VERSION 5.7 ;
  NOWIREEXTENSIONATPIN ON ;
  DIVIDERCHAR "/" ;
  BUSBITCHARS "[]" ;
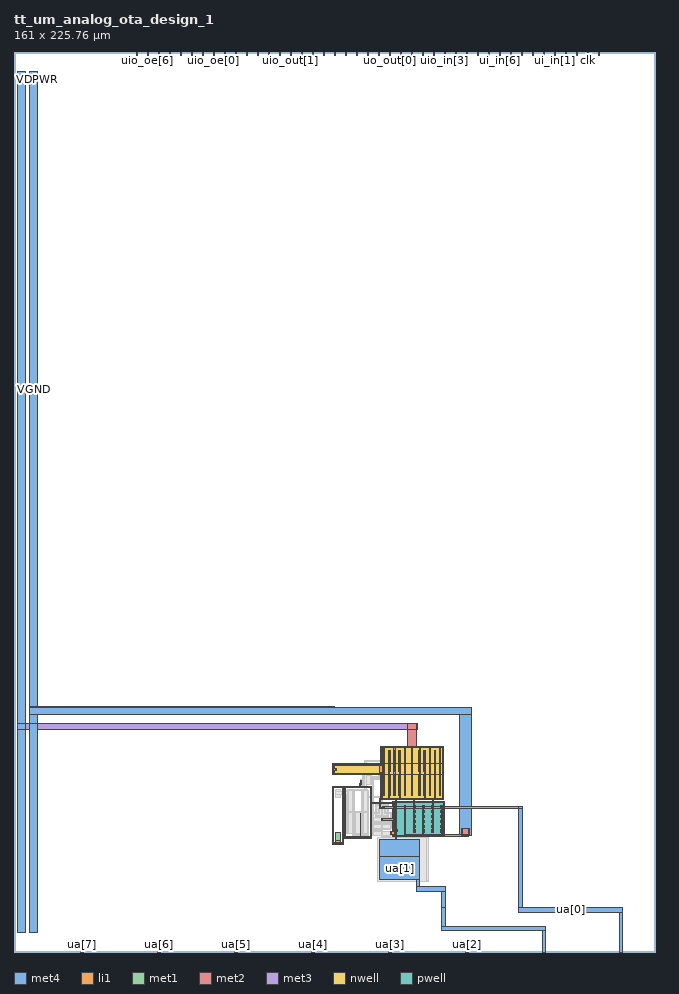
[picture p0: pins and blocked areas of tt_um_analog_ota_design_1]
MACRO tt_um_analog_ota_design_1
  CLASS BLOCK ;
  FOREIGN tt_um_analog_ota_design_1 ;
  ORIGIN 0.000 0.000 ;
  SIZE 161.000 BY 225.760 ;
  PIN clk
    DIRECTION INPUT ;
    USE SIGNAL ;
    PORT
      LAYER met4 ;
        RECT 143.830 224.760 144.130 225.760 ;
    END
  END clk
  PIN ena
    DIRECTION INPUT ;
    USE SIGNAL ;
    PORT
      LAYER met4 ;
        RECT 146.590 224.760 146.890 225.760 ;
    END
  END ena
  PIN rst_n
    DIRECTION INPUT ;
    USE SIGNAL ;
    PORT
      LAYER met4 ;
        RECT 141.070 224.760 141.370 225.760 ;
    END
  END rst_n
  PIN ua[0]
    DIRECTION INOUT ;
    USE SIGNAL ;
    ANTENNAGATEAREA 0.625000 ;
    PORT
      LAYER li1 ;
        RECT 92.460 36.145 92.960 36.315 ;
      LAYER met1 ;
        RECT 92.535 36.345 92.895 36.360 ;
        RECT 92.480 36.115 92.940 36.345 ;
        RECT 92.535 36.100 92.895 36.115 ;
      LAYER met2 ;
        RECT 92.585 36.040 92.865 36.420 ;
      LAYER met3 ;
        RECT 92.535 36.065 127.590 36.395 ;
        RECT 126.580 36.060 127.590 36.065 ;
      LAYER met4 ;
        RECT 126.625 36.055 127.545 36.400 ;
        RECT 126.630 11.280 127.530 36.055 ;
        RECT 126.630 11.180 133.390 11.280 ;
        RECT 126.630 10.010 152.705 11.180 ;
        RECT 151.810 0.000 152.710 10.010 ;
    END
  END ua[0]
  PIN ua[1]
    DIRECTION INOUT ;
    USE SIGNAL ;
    ANTENNAGATEAREA 0.625000 ;
    ANTENNADIFFAREA 15.688999 ;
    PORT
      LAYER li1 ;
        RECT 94.070 45.245 94.240 50.585 ;
        RECT 96.650 45.245 96.820 50.585 ;
        RECT 102.930 45.245 103.100 50.585 ;
        RECT 105.510 45.245 105.680 50.585 ;
        RECT 94.070 39.305 94.240 44.645 ;
        RECT 96.650 39.305 96.820 44.645 ;
        RECT 102.930 39.305 103.100 44.645 ;
        RECT 105.510 39.305 105.680 44.645 ;
        RECT 91.670 36.145 92.170 36.315 ;
        RECT 95.755 36.015 95.925 36.705 ;
        RECT 100.335 36.015 100.505 36.705 ;
        RECT 104.915 36.015 105.085 36.705 ;
        RECT 95.755 34.815 95.925 35.505 ;
        RECT 100.335 34.815 100.505 35.505 ;
        RECT 104.915 34.815 105.085 35.505 ;
        RECT 95.755 33.615 95.925 34.305 ;
        RECT 100.335 33.615 100.505 34.305 ;
        RECT 104.915 33.615 105.085 34.305 ;
        RECT 95.755 32.415 95.925 33.105 ;
        RECT 100.335 32.415 100.505 33.105 ;
        RECT 104.915 32.415 105.085 33.105 ;
        RECT 95.755 31.215 95.925 31.905 ;
        RECT 100.335 31.215 100.505 31.905 ;
        RECT 104.915 31.215 105.085 31.905 ;
        RECT 95.755 30.015 95.925 30.705 ;
        RECT 100.335 30.015 100.505 30.705 ;
        RECT 104.915 30.015 105.085 30.705 ;
      LAYER met1 ;
        RECT 94.040 50.550 94.270 50.565 ;
        RECT 96.620 50.550 96.850 50.565 ;
        RECT 102.900 50.550 103.130 50.565 ;
        RECT 105.480 50.550 105.710 50.565 ;
        RECT 93.975 45.280 94.335 50.550 ;
        RECT 96.555 45.280 96.915 50.550 ;
        RECT 102.835 45.280 103.195 50.550 ;
        RECT 105.415 45.280 105.775 50.550 ;
        RECT 94.040 45.265 94.270 45.280 ;
        RECT 96.620 45.265 96.850 45.280 ;
        RECT 102.900 45.265 103.130 45.280 ;
        RECT 105.480 45.265 105.710 45.280 ;
        RECT 94.040 44.610 94.270 44.625 ;
        RECT 96.620 44.610 96.850 44.625 ;
        RECT 102.900 44.610 103.130 44.625 ;
        RECT 105.480 44.610 105.710 44.625 ;
        RECT 93.975 39.340 94.335 44.610 ;
        RECT 96.555 39.340 96.915 44.610 ;
        RECT 102.835 39.340 103.195 44.610 ;
        RECT 105.415 39.340 105.775 44.610 ;
        RECT 94.040 39.325 94.270 39.340 ;
        RECT 96.620 39.325 96.850 39.340 ;
        RECT 102.900 39.325 103.130 39.340 ;
        RECT 105.480 39.325 105.710 39.340 ;
        RECT 95.725 36.625 95.955 36.685 ;
        RECT 100.305 36.625 100.535 36.685 ;
        RECT 104.885 36.625 105.115 36.685 ;
        RECT 91.735 36.345 92.095 36.360 ;
        RECT 91.690 36.115 92.150 36.345 ;
        RECT 91.735 36.100 92.095 36.115 ;
        RECT 95.660 36.095 96.020 36.625 ;
        RECT 100.240 36.095 100.600 36.625 ;
        RECT 104.820 36.095 105.180 36.625 ;
        RECT 95.725 36.035 95.955 36.095 ;
        RECT 100.305 36.035 100.535 36.095 ;
        RECT 104.885 36.035 105.115 36.095 ;
        RECT 95.725 35.425 95.955 35.485 ;
        RECT 100.305 35.425 100.535 35.485 ;
        RECT 104.885 35.425 105.115 35.485 ;
        RECT 95.660 34.895 96.020 35.425 ;
        RECT 100.240 34.895 100.600 35.425 ;
        RECT 104.820 34.895 105.180 35.425 ;
        RECT 95.725 34.835 95.955 34.895 ;
        RECT 100.305 34.835 100.535 34.895 ;
        RECT 104.885 34.835 105.115 34.895 ;
        RECT 95.725 34.225 95.955 34.285 ;
        RECT 100.305 34.225 100.535 34.285 ;
        RECT 104.885 34.225 105.115 34.285 ;
        RECT 95.660 33.695 96.020 34.225 ;
        RECT 100.240 33.695 100.600 34.225 ;
        RECT 104.820 33.695 105.180 34.225 ;
        RECT 95.725 33.635 95.955 33.695 ;
        RECT 100.305 33.635 100.535 33.695 ;
        RECT 104.885 33.635 105.115 33.695 ;
        RECT 95.725 33.025 95.955 33.085 ;
        RECT 100.305 33.025 100.535 33.085 ;
        RECT 104.885 33.025 105.115 33.085 ;
        RECT 95.660 32.495 96.020 33.025 ;
        RECT 100.240 32.495 100.600 33.025 ;
        RECT 104.820 32.495 105.180 33.025 ;
        RECT 95.725 32.435 95.955 32.495 ;
        RECT 100.305 32.435 100.535 32.495 ;
        RECT 104.885 32.435 105.115 32.495 ;
        RECT 95.725 31.825 95.955 31.885 ;
        RECT 100.305 31.825 100.535 31.885 ;
        RECT 104.885 31.825 105.115 31.885 ;
        RECT 95.660 31.295 96.020 31.825 ;
        RECT 100.240 31.295 100.600 31.825 ;
        RECT 104.820 31.295 105.180 31.825 ;
        RECT 95.725 31.235 95.955 31.295 ;
        RECT 100.305 31.235 100.535 31.295 ;
        RECT 104.885 31.235 105.115 31.295 ;
        RECT 95.725 30.625 95.955 30.685 ;
        RECT 100.305 30.625 100.535 30.685 ;
        RECT 104.885 30.625 105.115 30.685 ;
        RECT 95.660 30.095 96.020 30.625 ;
        RECT 100.240 30.095 100.600 30.625 ;
        RECT 104.820 30.095 105.180 30.625 ;
        RECT 95.725 30.035 95.955 30.095 ;
        RECT 100.305 30.035 100.535 30.095 ;
        RECT 104.885 30.035 105.115 30.095 ;
      LAYER met2 ;
        RECT 94.025 38.540 94.285 50.600 ;
        RECT 96.605 38.540 96.865 50.600 ;
        RECT 102.885 38.540 103.145 50.600 ;
        RECT 105.465 38.540 105.725 50.600 ;
        RECT 91.785 38.280 105.725 38.540 ;
        RECT 91.785 36.410 92.005 38.280 ;
        RECT 91.785 36.050 92.045 36.410 ;
        RECT 95.710 30.550 95.970 38.280 ;
        RECT 95.700 30.170 95.980 30.550 ;
        RECT 95.710 30.045 95.970 30.170 ;
        RECT 100.290 30.045 100.550 38.280 ;
        RECT 104.870 30.045 105.130 38.280 ;
      LAYER met3 ;
        RECT 95.590 30.110 96.090 30.610 ;
      LAYER met4 ;
        RECT 95.675 30.195 96.005 30.525 ;
        RECT 95.680 28.265 96.000 30.195 ;
        RECT 91.655 23.870 101.765 28.265 ;
        RECT 91.655 18.155 101.835 23.870 ;
        RECT 100.935 16.345 101.835 18.155 ;
        RECT 100.935 15.120 108.210 16.345 ;
        RECT 107.310 11.280 108.210 15.120 ;
        RECT 107.290 6.440 108.210 11.280 ;
        RECT 132.490 6.440 133.390 6.445 ;
        RECT 107.280 5.315 133.395 6.440 ;
        RECT 107.290 5.305 108.210 5.315 ;
        RECT 132.490 0.000 133.390 5.315 ;
    END
  END ua[1]
  PIN ua[2]
    DIRECTION INOUT ;
    USE SIGNAL ;
    PORT
      LAYER met4 ;
        RECT 113.170 0.000 114.070 1.000 ;
    END
  END ua[2]
  PIN ua[3]
    DIRECTION INOUT ;
    USE SIGNAL ;
    PORT
      LAYER met4 ;
        RECT 93.850 0.000 94.750 1.000 ;
    END
  END ua[3]
  PIN ua[4]
    DIRECTION INOUT ;
    USE SIGNAL ;
    PORT
      LAYER met4 ;
        RECT 74.530 0.000 75.430 1.000 ;
    END
  END ua[4]
  PIN ua[5]
    DIRECTION INOUT ;
    USE SIGNAL ;
    PORT
      LAYER met4 ;
        RECT 55.210 0.000 56.110 1.000 ;
    END
  END ua[5]
  PIN ua[6]
    DIRECTION INOUT ;
    USE SIGNAL ;
    PORT
      LAYER met4 ;
        RECT 35.890 0.000 36.790 1.000 ;
    END
  END ua[6]
  PIN ua[7]
    DIRECTION INOUT ;
    USE SIGNAL ;
    PORT
      LAYER met4 ;
        RECT 16.570 0.000 17.470 1.000 ;
    END
  END ua[7]
  PIN ui_in[0]
    DIRECTION INPUT ;
    USE SIGNAL ;
    PORT
      LAYER met4 ;
        RECT 138.310 224.760 138.610 225.760 ;
    END
  END ui_in[0]
  PIN ui_in[1]
    DIRECTION INPUT ;
    USE SIGNAL ;
    PORT
      LAYER met4 ;
        RECT 135.550 224.760 135.850 225.760 ;
    END
  END ui_in[1]
  PIN ui_in[2]
    DIRECTION INPUT ;
    USE SIGNAL ;
    PORT
      LAYER met4 ;
        RECT 132.790 224.760 133.090 225.760 ;
    END
  END ui_in[2]
  PIN ui_in[3]
    DIRECTION INPUT ;
    USE SIGNAL ;
    PORT
      LAYER met4 ;
        RECT 130.030 224.760 130.330 225.760 ;
    END
  END ui_in[3]
  PIN ui_in[4]
    DIRECTION INPUT ;
    USE SIGNAL ;
    PORT
      LAYER met4 ;
        RECT 127.270 224.760 127.570 225.760 ;
    END
  END ui_in[4]
  PIN ui_in[5]
    DIRECTION INPUT ;
    USE SIGNAL ;
    PORT
      LAYER met4 ;
        RECT 124.510 224.760 124.810 225.760 ;
    END
  END ui_in[5]
  PIN ui_in[6]
    DIRECTION INPUT ;
    USE SIGNAL ;
    PORT
      LAYER met4 ;
        RECT 121.750 224.760 122.050 225.760 ;
    END
  END ui_in[6]
  PIN ui_in[7]
    DIRECTION INPUT ;
    USE SIGNAL ;
    PORT
      LAYER met4 ;
        RECT 118.990 224.760 119.290 225.760 ;
    END
  END ui_in[7]
  PIN uio_in[0]
    DIRECTION INPUT ;
    USE SIGNAL ;
    PORT
      LAYER met4 ;
        RECT 116.230 224.760 116.530 225.760 ;
    END
  END uio_in[0]
  PIN uio_in[1]
    DIRECTION INPUT ;
    USE SIGNAL ;
    PORT
      LAYER met4 ;
        RECT 113.470 224.760 113.770 225.760 ;
    END
  END uio_in[1]
  PIN uio_in[2]
    DIRECTION INPUT ;
    USE SIGNAL ;
    PORT
      LAYER met4 ;
        RECT 110.710 224.760 111.010 225.760 ;
    END
  END uio_in[2]
  PIN uio_in[3]
    DIRECTION INPUT ;
    USE SIGNAL ;
    PORT
      LAYER met4 ;
        RECT 107.950 224.760 108.250 225.760 ;
    END
  END uio_in[3]
  PIN uio_in[4]
    DIRECTION INPUT ;
    USE SIGNAL ;
    PORT
      LAYER met4 ;
        RECT 105.190 224.760 105.490 225.760 ;
    END
  END uio_in[4]
  PIN uio_in[5]
    DIRECTION INPUT ;
    USE SIGNAL ;
    PORT
      LAYER met4 ;
        RECT 102.430 224.760 102.730 225.760 ;
    END
  END uio_in[5]
  PIN uio_in[6]
    DIRECTION INPUT ;
    USE SIGNAL ;
    PORT
      LAYER met4 ;
        RECT 99.670 224.760 99.970 225.760 ;
    END
  END uio_in[6]
  PIN uio_in[7]
    DIRECTION INPUT ;
    USE SIGNAL ;
    PORT
      LAYER met4 ;
        RECT 96.910 224.760 97.210 225.760 ;
    END
  END uio_in[7]
  PIN uio_oe[0]
    DIRECTION OUTPUT ;
    USE SIGNAL ;
    PORT
      LAYER met4 ;
        RECT 49.990 224.760 50.290 225.760 ;
    END
  END uio_oe[0]
  PIN uio_oe[1]
    DIRECTION OUTPUT ;
    USE SIGNAL ;
    PORT
      LAYER met4 ;
        RECT 47.230 224.760 47.530 225.760 ;
    END
  END uio_oe[1]
  PIN uio_oe[2]
    DIRECTION OUTPUT ;
    USE SIGNAL ;
    PORT
      LAYER met4 ;
        RECT 44.470 224.760 44.770 225.760 ;
    END
  END uio_oe[2]
  PIN uio_oe[3]
    DIRECTION OUTPUT ;
    USE SIGNAL ;
    PORT
      LAYER met4 ;
        RECT 41.710 224.760 42.010 225.760 ;
    END
  END uio_oe[3]
  PIN uio_oe[4]
    DIRECTION OUTPUT ;
    USE SIGNAL ;
    PORT
      LAYER met4 ;
        RECT 38.950 224.760 39.250 225.760 ;
    END
  END uio_oe[4]
  PIN uio_oe[5]
    DIRECTION OUTPUT ;
    USE SIGNAL ;
    PORT
      LAYER met4 ;
        RECT 36.190 224.760 36.490 225.760 ;
    END
  END uio_oe[5]
  PIN uio_oe[6]
    DIRECTION OUTPUT ;
    USE SIGNAL ;
    PORT
      LAYER met4 ;
        RECT 33.430 224.760 33.730 225.760 ;
    END
  END uio_oe[6]
  PIN uio_oe[7]
    DIRECTION OUTPUT ;
    USE SIGNAL ;
    PORT
      LAYER met4 ;
        RECT 30.670 224.760 30.970 225.760 ;
    END
  END uio_oe[7]
  PIN uio_out[0]
    DIRECTION OUTPUT ;
    USE SIGNAL ;
    PORT
      LAYER met4 ;
        RECT 72.070 224.760 72.370 225.760 ;
    END
  END uio_out[0]
  PIN uio_out[1]
    DIRECTION OUTPUT ;
    USE SIGNAL ;
    PORT
      LAYER met4 ;
        RECT 69.310 224.760 69.610 225.760 ;
    END
  END uio_out[1]
  PIN uio_out[2]
    DIRECTION OUTPUT ;
    USE SIGNAL ;
    PORT
      LAYER met4 ;
        RECT 66.550 224.760 66.850 225.760 ;
    END
  END uio_out[2]
  PIN uio_out[3]
    DIRECTION OUTPUT ;
    USE SIGNAL ;
    PORT
      LAYER met4 ;
        RECT 63.790 224.760 64.090 225.760 ;
    END
  END uio_out[3]
  PIN uio_out[4]
    DIRECTION OUTPUT ;
    USE SIGNAL ;
    PORT
      LAYER met4 ;
        RECT 61.030 224.760 61.330 225.760 ;
    END
  END uio_out[4]
  PIN uio_out[5]
    DIRECTION OUTPUT ;
    USE SIGNAL ;
    PORT
      LAYER met4 ;
        RECT 58.270 224.760 58.570 225.760 ;
    END
  END uio_out[5]
  PIN uio_out[6]
    DIRECTION OUTPUT ;
    USE SIGNAL ;
    PORT
      LAYER met4 ;
        RECT 55.510 224.760 55.810 225.760 ;
    END
  END uio_out[6]
  PIN uio_out[7]
    DIRECTION OUTPUT ;
    USE SIGNAL ;
    PORT
      LAYER met4 ;
        RECT 52.750 224.760 53.050 225.760 ;
    END
  END uio_out[7]
  PIN uo_out[0]
    DIRECTION OUTPUT ;
    USE SIGNAL ;
    PORT
      LAYER met4 ;
        RECT 94.150 224.760 94.450 225.760 ;
    END
  END uo_out[0]
  PIN uo_out[1]
    DIRECTION OUTPUT ;
    USE SIGNAL ;
    PORT
      LAYER met4 ;
        RECT 91.390 224.760 91.690 225.760 ;
    END
  END uo_out[1]
  PIN uo_out[2]
    DIRECTION OUTPUT ;
    USE SIGNAL ;
    PORT
      LAYER met4 ;
        RECT 88.630 224.760 88.930 225.760 ;
    END
  END uo_out[2]
  PIN uo_out[3]
    DIRECTION OUTPUT ;
    USE SIGNAL ;
    PORT
      LAYER met4 ;
        RECT 85.870 224.760 86.170 225.760 ;
    END
  END uo_out[3]
  PIN uo_out[4]
    DIRECTION OUTPUT ;
    USE SIGNAL ;
    PORT
      LAYER met4 ;
        RECT 83.110 224.760 83.410 225.760 ;
    END
  END uo_out[4]
  PIN uo_out[5]
    DIRECTION OUTPUT ;
    USE SIGNAL ;
    PORT
      LAYER met4 ;
        RECT 80.350 224.760 80.650 225.760 ;
    END
  END uo_out[5]
  PIN uo_out[6]
    DIRECTION OUTPUT ;
    USE SIGNAL ;
    PORT
      LAYER met4 ;
        RECT 77.590 224.760 77.890 225.760 ;
    END
  END uo_out[6]
  PIN uo_out[7]
    DIRECTION OUTPUT ;
    USE SIGNAL ;
    PORT
      LAYER met4 ;
        RECT 74.830 224.760 75.130 225.760 ;
    END
  END uo_out[7]
  PIN VDPWR
    DIRECTION INOUT ;
    USE POWER ;
    PORT
      LAYER nwell ;
        RECT 91.965 47.170 107.795 51.660 ;
        RECT 79.975 44.540 107.795 47.170 ;
        RECT 91.965 38.280 107.795 44.540 ;
      LAYER li1 ;
        RECT 92.145 51.310 107.615 51.480 ;
        RECT 80.155 46.820 91.875 46.990 ;
        RECT 80.155 46.125 80.325 46.820 ;
        RECT 91.705 46.690 91.875 46.820 ;
        RECT 92.145 46.690 92.315 51.310 ;
        RECT 80.155 45.585 80.950 46.125 ;
        RECT 80.155 44.890 80.325 45.585 ;
        RECT 91.705 45.020 92.315 46.690 ;
        RECT 95.360 45.245 95.530 50.585 ;
        RECT 97.940 45.245 98.110 50.585 ;
        RECT 99.790 45.245 99.960 50.585 ;
        RECT 101.640 45.245 101.810 50.585 ;
        RECT 104.220 45.245 104.390 50.585 ;
        RECT 106.800 45.245 106.970 50.585 ;
        RECT 91.705 44.890 91.875 45.020 ;
        RECT 80.155 44.720 91.875 44.890 ;
        RECT 92.145 38.630 92.315 45.020 ;
        RECT 92.780 39.305 92.950 44.645 ;
        RECT 95.360 39.305 95.530 44.645 ;
        RECT 97.940 39.305 98.110 44.645 ;
        RECT 99.790 39.305 99.960 44.645 ;
        RECT 101.640 39.305 101.810 44.645 ;
        RECT 104.220 39.305 104.390 44.645 ;
        RECT 106.800 39.305 106.970 44.645 ;
        RECT 107.445 38.630 107.615 51.310 ;
        RECT 92.145 38.460 107.615 38.630 ;
      LAYER met1 ;
        RECT 92.685 51.510 107.065 51.525 ;
        RECT 92.675 51.280 107.075 51.510 ;
        RECT 92.685 51.265 107.065 51.280 ;
        RECT 95.330 50.550 95.560 50.565 ;
        RECT 97.910 50.550 98.140 50.565 ;
        RECT 99.760 50.550 99.990 50.565 ;
        RECT 101.610 50.550 101.840 50.565 ;
        RECT 104.190 50.550 104.420 50.565 ;
        RECT 106.770 50.550 107.000 50.565 ;
        RECT 80.750 45.605 80.980 46.105 ;
        RECT 95.265 45.280 95.625 50.550 ;
        RECT 97.845 45.280 98.205 50.550 ;
        RECT 99.695 45.280 100.055 50.550 ;
        RECT 101.545 45.280 101.905 50.550 ;
        RECT 104.125 45.280 104.485 50.550 ;
        RECT 106.705 45.280 107.065 50.550 ;
        RECT 95.330 45.265 95.560 45.280 ;
        RECT 97.910 45.265 98.140 45.280 ;
        RECT 99.760 45.265 99.990 45.280 ;
        RECT 101.610 45.265 101.840 45.280 ;
        RECT 104.190 45.265 104.420 45.280 ;
        RECT 106.770 45.265 107.000 45.280 ;
        RECT 92.750 44.610 92.980 44.625 ;
        RECT 95.330 44.610 95.560 44.625 ;
        RECT 97.910 44.610 98.140 44.625 ;
        RECT 99.760 44.610 99.990 44.625 ;
        RECT 101.610 44.610 101.840 44.625 ;
        RECT 104.190 44.610 104.420 44.625 ;
        RECT 106.770 44.610 107.000 44.625 ;
        RECT 92.685 39.340 93.045 44.610 ;
        RECT 95.265 39.340 95.625 44.610 ;
        RECT 97.845 39.340 98.205 44.610 ;
        RECT 99.695 39.340 100.055 44.610 ;
        RECT 101.545 39.340 101.905 44.610 ;
        RECT 104.125 39.340 104.485 44.610 ;
        RECT 106.705 39.340 107.065 44.610 ;
        RECT 92.750 39.325 92.980 39.340 ;
        RECT 95.330 39.325 95.560 39.340 ;
        RECT 97.910 39.325 98.140 39.340 ;
        RECT 99.760 39.325 99.990 39.340 ;
        RECT 101.610 39.325 101.840 39.340 ;
        RECT 104.190 39.325 104.420 39.340 ;
        RECT 106.770 39.325 107.000 39.340 ;
      LAYER met2 ;
        RECT 98.605 51.575 101.060 57.195 ;
        RECT 92.735 51.215 107.015 51.575 ;
        RECT 92.735 39.290 92.995 51.215 ;
        RECT 95.315 39.290 95.575 51.215 ;
        RECT 97.895 39.290 98.155 51.215 ;
        RECT 99.745 39.290 100.005 51.215 ;
        RECT 101.595 39.290 101.855 51.215 ;
        RECT 104.175 39.290 104.435 51.215 ;
        RECT 106.755 39.290 107.015 51.215 ;
      LAYER met3 ;
        RECT 1.000 57.430 101.165 57.440 ;
        RECT 0.950 55.935 101.165 57.430 ;
        RECT 80.340 55.810 101.165 55.935 ;
      LAYER met4 ;
        RECT 1.000 57.435 3.000 220.760 ;
        RECT 0.995 55.930 3.000 57.435 ;
        RECT 1.000 5.000 3.000 55.930 ;
    END
  END VDPWR
  PIN VGND
    DIRECTION INOUT ;
    USE GROUND ;
    PORT
      LAYER pwell ;
        RECT 79.800 41.145 82.770 41.575 ;
        RECT 79.800 27.485 80.230 41.145 ;
        RECT 82.340 27.485 82.770 41.145 ;
        RECT 82.780 41.145 89.740 41.575 ;
        RECT 82.780 28.895 83.210 41.145 ;
        RECT 89.310 28.895 89.740 41.145 ;
        RECT 95.055 29.035 108.075 37.685 ;
        RECT 82.780 28.465 89.740 28.895 ;
        RECT 79.800 27.055 82.770 27.485 ;
      LAYER li1 ;
        RECT 87.035 42.250 87.205 43.060 ;
        RECT 86.760 42.020 87.205 42.250 ;
        RECT 86.760 41.445 86.990 42.020 ;
        RECT 79.930 41.275 89.610 41.445 ;
        RECT 79.930 27.355 80.100 41.275 ;
        RECT 80.580 27.355 81.990 29.995 ;
        RECT 82.470 28.765 83.080 41.275 ;
        RECT 86.830 28.765 87.000 34.775 ;
        RECT 89.440 28.765 89.610 41.275 ;
        RECT 95.185 37.385 107.945 37.555 ;
        RECT 92.230 32.910 92.400 33.600 ;
        RECT 95.185 30.120 95.355 37.385 ;
        RECT 98.045 36.015 98.215 36.705 ;
        RECT 102.625 36.015 102.795 36.705 ;
        RECT 107.205 36.015 107.375 36.705 ;
        RECT 98.045 34.815 98.215 35.505 ;
        RECT 102.625 34.815 102.795 35.505 ;
        RECT 107.205 34.815 107.375 35.505 ;
        RECT 98.045 33.615 98.215 34.305 ;
        RECT 102.625 33.615 102.795 34.305 ;
        RECT 107.205 33.615 107.375 34.305 ;
        RECT 98.045 32.415 98.215 33.105 ;
        RECT 102.625 32.415 102.795 33.105 ;
        RECT 107.205 32.415 107.375 33.105 ;
        RECT 98.045 31.215 98.215 31.905 ;
        RECT 102.625 31.215 102.795 31.905 ;
        RECT 107.205 31.215 107.375 31.905 ;
        RECT 94.520 29.430 95.355 30.120 ;
        RECT 98.045 30.015 98.215 30.705 ;
        RECT 102.625 30.015 102.795 30.705 ;
        RECT 107.205 30.015 107.375 30.705 ;
        RECT 95.185 29.335 95.355 29.430 ;
        RECT 107.775 29.335 107.945 37.385 ;
        RECT 95.185 29.165 107.945 29.335 ;
        RECT 82.470 28.595 89.610 28.765 ;
        RECT 82.470 27.355 82.640 28.595 ;
        RECT 79.930 27.185 82.640 27.355 ;
      LAYER met1 ;
        RECT 87.005 42.040 87.235 43.040 ;
        RECT 89.380 37.355 95.415 37.585 ;
        RECT 98.015 36.625 98.245 36.685 ;
        RECT 102.595 36.625 102.825 36.685 ;
        RECT 107.175 36.625 107.405 36.685 ;
        RECT 97.950 36.095 98.310 36.625 ;
        RECT 102.530 36.095 102.890 36.625 ;
        RECT 107.110 36.095 107.470 36.625 ;
        RECT 98.015 36.035 98.245 36.095 ;
        RECT 102.595 36.035 102.825 36.095 ;
        RECT 107.175 36.035 107.405 36.095 ;
        RECT 98.015 35.425 98.245 35.485 ;
        RECT 102.595 35.425 102.825 35.485 ;
        RECT 107.175 35.425 107.405 35.485 ;
        RECT 97.950 34.895 98.310 35.425 ;
        RECT 102.530 34.895 102.890 35.425 ;
        RECT 107.110 34.895 107.470 35.425 ;
        RECT 98.015 34.835 98.245 34.895 ;
        RECT 102.595 34.835 102.825 34.895 ;
        RECT 107.175 34.835 107.405 34.895 ;
        RECT 80.630 27.865 81.940 29.970 ;
        RECT 86.800 29.755 87.030 34.755 ;
        RECT 98.015 34.225 98.245 34.285 ;
        RECT 102.595 34.225 102.825 34.285 ;
        RECT 107.175 34.225 107.405 34.285 ;
        RECT 97.950 33.695 98.310 34.225 ;
        RECT 102.530 33.695 102.890 34.225 ;
        RECT 107.110 33.695 107.470 34.225 ;
        RECT 98.015 33.635 98.245 33.695 ;
        RECT 102.595 33.635 102.825 33.695 ;
        RECT 107.175 33.635 107.405 33.695 ;
        RECT 92.200 33.520 92.430 33.580 ;
        RECT 95.155 33.520 95.385 33.580 ;
        RECT 92.135 32.990 92.495 33.520 ;
        RECT 95.090 32.990 95.450 33.520 ;
        RECT 98.015 33.025 98.245 33.085 ;
        RECT 102.595 33.025 102.825 33.085 ;
        RECT 107.175 33.025 107.405 33.085 ;
        RECT 92.200 32.930 92.430 32.990 ;
        RECT 95.155 32.930 95.385 32.990 ;
        RECT 97.950 32.495 98.310 33.025 ;
        RECT 102.530 32.495 102.890 33.025 ;
        RECT 107.110 32.495 107.470 33.025 ;
        RECT 98.015 32.435 98.245 32.495 ;
        RECT 102.595 32.435 102.825 32.495 ;
        RECT 107.175 32.435 107.405 32.495 ;
        RECT 98.015 31.825 98.245 31.885 ;
        RECT 102.595 31.825 102.825 31.885 ;
        RECT 107.175 31.825 107.405 31.885 ;
        RECT 97.950 31.295 98.310 31.825 ;
        RECT 102.530 31.295 102.890 31.825 ;
        RECT 107.110 31.295 107.470 31.825 ;
        RECT 98.015 31.235 98.245 31.295 ;
        RECT 102.595 31.235 102.825 31.295 ;
        RECT 107.175 31.235 107.405 31.295 ;
        RECT 98.015 30.625 98.245 30.685 ;
        RECT 102.595 30.625 102.825 30.685 ;
        RECT 107.175 30.625 107.405 30.685 ;
        RECT 94.490 29.450 94.720 30.100 ;
        RECT 97.950 30.095 98.310 30.625 ;
        RECT 102.530 30.095 102.890 30.625 ;
        RECT 107.110 30.095 107.470 30.625 ;
        RECT 98.015 30.035 98.245 30.095 ;
        RECT 102.595 30.035 102.825 30.095 ;
        RECT 107.175 30.035 107.405 30.095 ;
        RECT 97.940 29.365 107.515 29.380 ;
        RECT 97.940 29.135 107.525 29.365 ;
        RECT 97.940 29.120 107.515 29.135 ;
      LAYER met2 ;
        RECT 92.185 33.520 92.445 33.570 ;
        RECT 95.140 33.520 95.400 33.570 ;
        RECT 92.185 32.990 95.400 33.520 ;
        RECT 92.185 32.940 92.445 32.990 ;
        RECT 95.140 32.940 95.400 32.990 ;
        RECT 98.000 29.430 98.260 36.675 ;
        RECT 102.580 29.430 102.840 36.675 ;
        RECT 107.160 29.430 107.420 36.675 ;
        RECT 112.425 29.430 114.115 30.880 ;
        RECT 98.000 29.070 114.115 29.430 ;
      LAYER met3 ;
        RECT 112.375 29.335 114.165 30.855 ;
      LAYER met4 ;
        RECT 4.000 61.460 6.000 220.760 ;
        RECT 4.000 61.455 80.435 61.460 ;
        RECT 4.000 59.455 114.785 61.455 ;
        RECT 4.000 5.000 6.000 59.455 ;
        RECT 111.825 29.100 114.785 59.455 ;
    END
  END VGND
  OBS
      LAYER pwell ;
        RECT 86.845 41.910 87.835 43.170 ;
        RECT 87.900 41.910 89.740 44.170 ;
        RECT 83.500 29.625 85.340 40.435 ;
        RECT 85.350 29.625 87.190 34.885 ;
        RECT 87.200 29.625 89.040 40.435 ;
      LAYER nwell ;
        RECT 90.690 33.920 93.940 37.010 ;
      LAYER pwell ;
        RECT 89.750 32.800 94.880 33.710 ;
        RECT 89.750 31.060 94.880 31.970 ;
        RECT 89.750 29.320 94.880 30.230 ;
      LAYER li1 ;
        RECT 94.300 50.800 106.885 50.970 ;
        RECT 81.010 46.340 91.010 46.510 ;
        RECT 91.070 45.585 91.240 46.125 ;
        RECT 81.010 45.200 91.010 45.370 ;
        RECT 98.500 45.245 98.670 50.585 ;
        RECT 101.080 45.245 101.250 50.585 ;
        RECT 93.010 44.860 106.885 45.030 ;
        RECT 88.320 44.230 89.320 44.400 ;
        RECT 87.475 42.020 87.645 43.060 ;
        RECT 88.090 42.020 88.260 44.060 ;
        RECT 89.380 42.020 89.550 44.060 ;
        RECT 87.175 41.680 87.505 41.850 ;
        RECT 80.580 38.635 81.990 40.795 ;
        RECT 83.775 40.495 88.765 40.665 ;
        RECT 83.690 35.285 83.860 40.325 ;
        RECT 84.980 35.285 85.150 40.325 ;
        RECT 87.390 35.285 87.560 40.325 ;
        RECT 88.680 35.285 88.850 40.325 ;
        RECT 98.500 39.305 98.670 44.645 ;
        RECT 101.080 39.305 101.250 44.645 ;
        RECT 92.865 38.920 106.885 39.090 ;
        RECT 95.840 36.875 107.290 37.045 ;
        RECT 90.870 36.660 93.760 36.830 ;
        RECT 83.775 34.945 88.765 35.115 ;
        RECT 83.690 29.735 83.860 34.775 ;
        RECT 84.980 29.735 85.150 34.775 ;
        RECT 85.540 29.735 85.710 34.775 ;
        RECT 87.390 29.735 87.560 34.775 ;
        RECT 88.680 29.735 88.850 34.775 ;
        RECT 90.870 34.270 91.040 36.660 ;
        RECT 91.440 34.640 91.610 35.930 ;
        RECT 92.230 34.640 92.400 35.930 ;
        RECT 93.020 34.640 93.190 35.930 ;
        RECT 93.590 34.270 93.760 36.660 ;
        RECT 95.840 35.675 107.290 35.845 ;
        RECT 95.840 34.475 107.290 34.645 ;
        RECT 90.870 34.100 93.760 34.270 ;
        RECT 89.940 32.910 90.110 33.600 ;
        RECT 94.520 32.910 94.690 33.600 ;
        RECT 95.840 33.275 107.290 33.445 ;
        RECT 90.170 32.570 92.170 32.740 ;
        RECT 92.460 32.570 94.460 32.740 ;
        RECT 95.840 32.075 107.290 32.245 ;
        RECT 89.940 31.170 90.110 31.860 ;
        RECT 92.230 31.170 92.400 31.860 ;
        RECT 94.520 31.170 94.690 31.860 ;
        RECT 90.170 30.830 92.170 31.000 ;
        RECT 92.460 30.830 94.460 31.000 ;
        RECT 95.840 30.875 107.290 31.045 ;
        RECT 90.170 30.290 92.170 30.460 ;
        RECT 89.940 29.430 90.110 30.120 ;
        RECT 92.230 29.430 92.400 30.120 ;
        RECT 95.840 29.675 107.290 29.845 ;
        RECT 92.460 29.090 94.460 29.260 ;
      LAYER met1 ;
        RECT 94.320 50.970 106.720 51.000 ;
        RECT 94.320 50.800 106.885 50.970 ;
        RECT 94.320 50.770 106.720 50.800 ;
        RECT 98.470 50.550 98.700 50.565 ;
        RECT 81.030 46.310 91.270 46.540 ;
        RECT 91.040 45.400 91.270 46.310 ;
        RECT 81.030 45.170 91.270 45.400 ;
        RECT 98.405 45.280 98.765 50.550 ;
        RECT 100.985 45.280 101.345 50.770 ;
        RECT 98.470 45.265 98.700 45.280 ;
        RECT 101.050 45.265 101.280 45.280 ;
        RECT 88.340 44.430 89.300 45.170 ;
        RECT 87.445 44.200 89.300 44.430 ;
        RECT 91.505 45.030 106.720 45.060 ;
        RECT 91.505 44.860 106.885 45.030 ;
        RECT 91.505 44.830 106.720 44.860 ;
        RECT 87.445 42.040 87.675 44.200 ;
        RECT 91.505 44.040 91.735 44.830 ;
        RECT 98.470 44.610 98.700 44.625 ;
        RECT 101.050 44.610 101.280 44.625 ;
        RECT 87.995 41.880 88.355 44.040 ;
        RECT 89.350 43.815 91.735 44.040 ;
        RECT 89.350 42.040 89.580 43.815 ;
        RECT 87.155 41.650 88.355 41.880 ;
        RECT 80.630 40.310 81.940 40.765 ;
        RECT 88.045 40.695 88.355 41.650 ;
        RECT 83.940 40.665 88.600 40.695 ;
        RECT 83.775 40.495 88.765 40.665 ;
        RECT 83.940 40.465 88.600 40.495 ;
        RECT 80.630 40.305 83.595 40.310 ;
        RECT 80.630 39.585 83.955 40.305 ;
        RECT 80.630 38.660 81.940 39.585 ;
        RECT 83.595 35.305 83.955 39.585 ;
        RECT 84.885 35.305 85.245 40.305 ;
        RECT 87.295 35.305 87.655 40.305 ;
        RECT 88.585 39.120 88.945 40.305 ;
        RECT 98.405 39.340 98.765 44.610 ;
        RECT 100.985 39.340 101.345 44.610 ;
        RECT 98.470 39.325 98.700 39.340 ;
        RECT 101.050 39.325 101.280 39.340 ;
        RECT 88.585 39.090 106.720 39.120 ;
        RECT 88.585 38.920 106.885 39.090 ;
        RECT 88.585 38.890 106.720 38.920 ;
        RECT 88.585 38.860 93.030 38.890 ;
        RECT 88.585 35.305 88.945 38.860 ;
        RECT 96.005 37.045 107.125 37.075 ;
        RECT 95.840 36.875 107.290 37.045 ;
        RECT 92.135 36.615 92.495 36.875 ;
        RECT 96.005 36.845 107.125 36.875 ;
        RECT 83.940 35.115 88.600 35.145 ;
        RECT 83.775 34.945 88.765 35.115 ;
        RECT 83.940 34.915 88.600 34.945 ;
        RECT 83.595 29.755 83.955 34.755 ;
        RECT 84.885 29.755 85.245 34.755 ;
        RECT 85.510 29.755 85.740 34.915 ;
        RECT 91.410 34.890 91.640 35.910 ;
        RECT 92.200 35.415 92.430 35.910 ;
        RECT 92.135 35.155 92.495 35.415 ;
        RECT 87.295 29.755 87.655 34.755 ;
        RECT 88.585 29.755 88.945 34.755 ;
        RECT 89.910 34.660 91.640 34.890 ;
        RECT 92.200 34.660 92.430 35.155 ;
        RECT 92.990 34.890 93.220 35.910 ;
        RECT 96.005 35.845 107.125 35.875 ;
        RECT 95.840 35.675 107.290 35.845 ;
        RECT 96.005 35.645 107.125 35.675 ;
        RECT 92.990 34.660 94.720 34.890 ;
        RECT 89.910 32.800 90.140 34.660 ;
        RECT 92.135 34.055 92.495 34.315 ;
        RECT 89.910 32.770 92.060 32.800 ;
        RECT 92.540 32.770 94.350 32.800 ;
        RECT 89.910 32.540 94.350 32.770 ;
        RECT 89.910 32.510 92.060 32.540 ;
        RECT 92.540 32.510 94.350 32.540 ;
        RECT 94.490 32.275 94.720 34.660 ;
        RECT 96.005 34.645 107.125 34.675 ;
        RECT 95.840 34.475 107.290 34.645 ;
        RECT 96.005 34.445 107.125 34.475 ;
        RECT 96.005 33.445 107.125 33.475 ;
        RECT 95.840 33.275 107.290 33.445 ;
        RECT 96.005 33.245 107.125 33.275 ;
        RECT 89.910 32.245 107.125 32.275 ;
        RECT 89.910 32.075 107.290 32.245 ;
        RECT 89.910 32.045 107.125 32.075 ;
        RECT 89.910 31.190 90.140 32.045 ;
        RECT 92.200 31.645 92.430 31.840 ;
        RECT 92.135 31.385 92.495 31.645 ;
        RECT 92.200 31.190 92.430 31.385 ;
        RECT 94.490 31.190 94.720 32.045 ;
        RECT 96.005 31.045 107.125 31.075 ;
        RECT 90.190 30.800 94.440 31.030 ;
        RECT 95.840 30.875 107.290 31.045 ;
        RECT 96.005 30.845 107.125 30.875 ;
        RECT 90.190 30.490 92.150 30.800 ;
        RECT 89.910 30.260 92.150 30.490 ;
        RECT 89.910 30.245 90.610 30.260 ;
        RECT 90.990 30.245 91.350 30.260 ;
        RECT 91.730 30.245 92.090 30.260 ;
        RECT 89.910 29.905 90.140 30.245 ;
        RECT 89.845 29.645 90.205 29.905 ;
        RECT 89.910 29.450 90.140 29.645 ;
        RECT 92.200 29.290 92.430 30.100 ;
        RECT 96.005 29.845 107.125 29.875 ;
        RECT 95.840 29.675 107.290 29.845 ;
        RECT 96.005 29.645 107.125 29.675 ;
        RECT 92.200 29.060 94.440 29.290 ;
      LAYER met2 ;
        RECT 98.455 48.110 98.715 50.600 ;
        RECT 98.445 47.730 98.725 48.110 ;
        RECT 98.455 45.250 98.715 47.730 ;
        RECT 101.035 45.250 101.295 50.600 ;
        RECT 88.045 41.180 88.305 44.090 ;
        RECT 83.645 40.545 87.605 40.805 ;
        RECT 88.035 40.800 88.315 41.180 ;
        RECT 98.455 40.890 98.715 44.640 ;
        RECT 101.035 43.535 101.295 44.640 ;
        RECT 101.025 43.155 101.305 43.535 ;
        RECT 83.645 29.705 83.905 40.545 ;
        RECT 84.935 29.565 85.195 40.355 ;
        RECT 87.345 29.705 87.605 40.545 ;
        RECT 98.445 40.510 98.725 40.890 ;
        RECT 88.635 29.565 88.895 40.355 ;
        RECT 98.455 39.290 98.715 40.510 ;
        RECT 101.035 39.290 101.295 43.155 ;
        RECT 92.175 37.545 92.455 37.925 ;
        RECT 92.185 34.005 92.445 37.545 ;
        RECT 92.175 31.325 92.455 31.705 ;
        RECT 89.885 29.585 90.165 29.965 ;
        RECT 84.935 29.305 88.895 29.565 ;
      LAYER met3 ;
        RECT 87.985 47.755 98.775 48.085 ;
        RECT 87.985 40.825 88.365 47.755 ;
        RECT 89.835 43.180 101.355 43.510 ;
        RECT 89.835 29.610 90.215 43.180 ;
        RECT 92.125 40.535 98.775 40.865 ;
        RECT 92.125 37.570 92.505 40.535 ;
        RECT 92.125 28.660 92.505 31.680 ;
        RECT 91.260 17.760 103.920 28.660 ;
      LAYER met4 ;
        RECT 103.420 17.820 103.900 28.600 ;
  END
END tt_um_analog_ota_design_1
END LIBRARY

